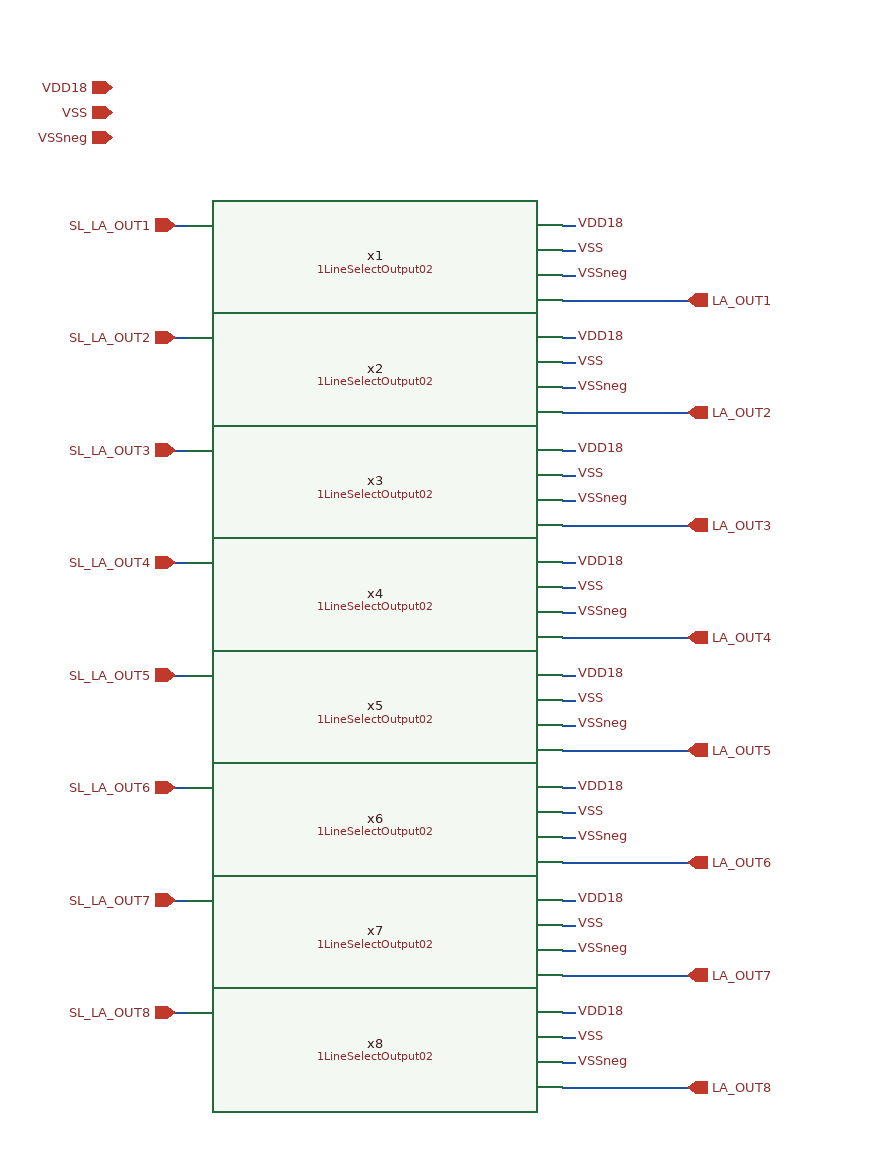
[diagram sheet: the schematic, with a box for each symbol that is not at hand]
v {xschem version=3.4.4 file_version=1.2
}
G {}
K {}
V {}
S {}
E {}
N 680 180 690 180 {
lab=VDD18}
N 680 200 690 200 {
lab=VSS}
N 680 220 690 220 {
lab=VSSneg}
N 680 270 690 270 {
lab=VDD18}
N 680 290 690 290 {
lab=VSS}
N 680 310 690 310 {
lab=VSSneg}
N 680 360 690 360 {
lab=VDD18}
N 680 380 690 380 {
lab=VSS}
N 680 400 690 400 {
lab=VSSneg}
N 680 450 690 450 {
lab=VDD18}
N 680 470 690 470 {
lab=VSS}
N 680 490 690 490 {
lab=VSSneg}
N 680 540 690 540 {
lab=VDD18}
N 680 560 690 560 {
lab=VSS}
N 680 580 690 580 {
lab=VSSneg}
N 680 630 690 630 {
lab=VDD18}
N 680 650 690 650 {
lab=VSS}
N 680 670 690 670 {
lab=VSSneg}
N 680 720 690 720 {
lab=VDD18}
N 680 740 690 740 {
lab=VSS}
N 680 760 690 760 {
lab=VSSneg}
N 680 810 690 810 {
lab=VDD18}
N 680 830 690 830 {
lab=VSS}
N 680 850 690 850 {
lab=VSSneg}
N 370 180 380 180 {
lab=SL_LA_OUT1}
N 370 270 380 270 {
lab=SL_LA_OUT2}
N 370 360 380 360 {
lab=SL_LA_OUT3}
N 370 450 380 450 {
lab=SL_LA_OUT4}
N 370 540 380 540 {
lab=SL_LA_OUT5}
N 370 630 380 630 {
lab=SL_LA_OUT6}
N 370 720 380 720 {
lab=SL_LA_OUT7}
N 370 810 380 810 {
lab=SL_LA_OUT8}
N 680 240 780 240 {
lab=LA_OUT1}
N 680 330 780 330 {
lab=LA_OUT1}
N 680 420 780 420 {
lab=LA_OUT3}
N 680 510 780 510 {
lab=LA_OUT4}
N 680 600 780 600 {
lab=LA_OUT5}
N 680 690 780 690 {
lab=LA_OUT6}
N 680 780 780 780 {
lab=LA_OUT7}
N 680 870 780 870 {
lab=LA_OUT8}
C {1LineSelectOutput02.sym} 530 210 0 0 {name=x1}
C {1LineSelectOutput02.sym} 530 300 0 0 {name=x2}
C {1LineSelectOutput02.sym} 530 390 0 0 {name=x3}
C {1LineSelectOutput02.sym} 530 480 0 0 {name=x4}
C {1LineSelectOutput02.sym} 530 570 0 0 {name=x5}
C {1LineSelectOutput02.sym} 530 660 0 0 {name=x6}
C {1LineSelectOutput02.sym} 530 750 0 0 {name=x7}
C {1LineSelectOutput02.sym} 530 840 0 0 {name=x8}
C {devices/lab_pin.sym} 690 180 2 0 {name=p5 sig_type=std_logic lab=VDD18}
C {devices/lab_pin.sym} 690 270 2 0 {name=p1 sig_type=std_logic lab=VDD18}
C {devices/lab_pin.sym} 690 360 2 0 {name=p2 sig_type=std_logic lab=VDD18}
C {devices/lab_pin.sym} 690 450 2 0 {name=p3 sig_type=std_logic lab=VDD18}
C {devices/lab_pin.sym} 690 540 2 0 {name=p4 sig_type=std_logic lab=VDD18}
C {devices/lab_pin.sym} 690 630 2 0 {name=p6 sig_type=std_logic lab=VDD18}
C {devices/lab_pin.sym} 690 720 2 0 {name=p7 sig_type=std_logic lab=VDD18}
C {devices/lab_pin.sym} 690 810 2 0 {name=p8 sig_type=std_logic lab=VDD18}
C {devices/lab_pin.sym} 690 200 2 0 {name=p9 sig_type=std_logic lab=VSS}
C {devices/lab_pin.sym} 690 290 2 0 {name=p10 sig_type=std_logic lab=VSS}
C {devices/lab_pin.sym} 690 380 2 0 {name=p11 sig_type=std_logic lab=VSS}
C {devices/lab_pin.sym} 690 470 2 0 {name=p12 sig_type=std_logic lab=VSS}
C {devices/lab_pin.sym} 690 560 2 0 {name=p13 sig_type=std_logic lab=VSS}
C {devices/lab_pin.sym} 690 650 2 0 {name=p14 sig_type=std_logic lab=VSS}
C {devices/lab_pin.sym} 690 740 2 0 {name=p15 sig_type=std_logic lab=VSS}
C {devices/lab_pin.sym} 690 830 2 0 {name=p16 sig_type=std_logic lab=VSS}
C {devices/lab_pin.sym} 690 850 2 0 {name=p17 sig_type=std_logic lab=VSSneg}
C {devices/lab_pin.sym} 690 760 2 0 {name=p18 sig_type=std_logic lab=VSSneg}
C {devices/lab_pin.sym} 690 670 2 0 {name=p19 sig_type=std_logic lab=VSSneg}
C {devices/lab_pin.sym} 690 580 2 0 {name=p20 sig_type=std_logic lab=VSSneg}
C {devices/lab_pin.sym} 690 490 2 0 {name=p21 sig_type=std_logic lab=VSSneg}
C {devices/lab_pin.sym} 690 400 2 0 {name=p22 sig_type=std_logic lab=VSSneg}
C {devices/lab_pin.sym} 690 310 2 0 {name=p23 sig_type=std_logic lab=VSSneg}
C {devices/lab_pin.sym} 690 220 2 0 {name=p24 sig_type=std_logic lab=VSSneg}
C {devices/ipin.sym} 370 180 0 0 {name=p25 lab=SL_LA_OUT1}
C {devices/ipin.sym} 370 270 0 0 {name=p26 lab=SL_LA_OUT2}
C {devices/ipin.sym} 370 360 0 0 {name=p27 lab=SL_LA_OUT3}
C {devices/ipin.sym} 370 450 0 0 {name=p28 lab=SL_LA_OUT4}
C {devices/ipin.sym} 370 540 0 0 {name=p29 lab=SL_LA_OUT5}
C {devices/ipin.sym} 370 630 0 0 {name=p30 lab=SL_LA_OUT6}
C {devices/ipin.sym} 370 720 0 0 {name=p31 lab=SL_LA_OUT7}
C {devices/ipin.sym} 370 810 0 0 {name=p32 lab=SL_LA_OUT8}
C {devices/iopin.sym} 320 70 2 0 {name=p33 lab=VDD18}
C {devices/iopin.sym} 320 90 2 0 {name=p34 lab=VSS}
C {devices/iopin.sym} 320 110 2 0 {name=p35 lab=VSSneg}
C {devices/opin.sym} 780 240 0 0 {name=p36 lab=LA_OUT1}
C {devices/opin.sym} 780 330 0 0 {name=p37 lab=LA_OUT2}
C {devices/opin.sym} 780 420 0 0 {name=p38 lab=LA_OUT3}
C {devices/opin.sym} 780 510 0 0 {name=p39 lab=LA_OUT4}
C {devices/opin.sym} 780 600 0 0 {name=p40 lab=LA_OUT5}
C {devices/opin.sym} 780 690 0 0 {name=p41 lab=LA_OUT6}
C {devices/opin.sym} 780 780 0 0 {name=p42 lab=LA_OUT7}
C {devices/opin.sym} 780 870 0 0 {name=p43 lab=LA_OUT8}
